###############################################################
#  Generated by:      Cadence Innovus 21.35-s114_1
#  OS:                Linux x86_64(Host ID CadenceRocky8)
#  Generated on:      Sat Mar  1 18:53:37 2025
#  Design:            scm_128x32
#  Command:           write_lef_abstract ram128_obspg.lef -obs_above_top_layer Metal4 -top_layer Metal3 -stripe_pins -pg_pin_layers {Metal4 Metal5}
###############################################################

VERSION 5.8 ;

BUSBITCHARS "[]" ;
DIVIDERCHAR "/" ;

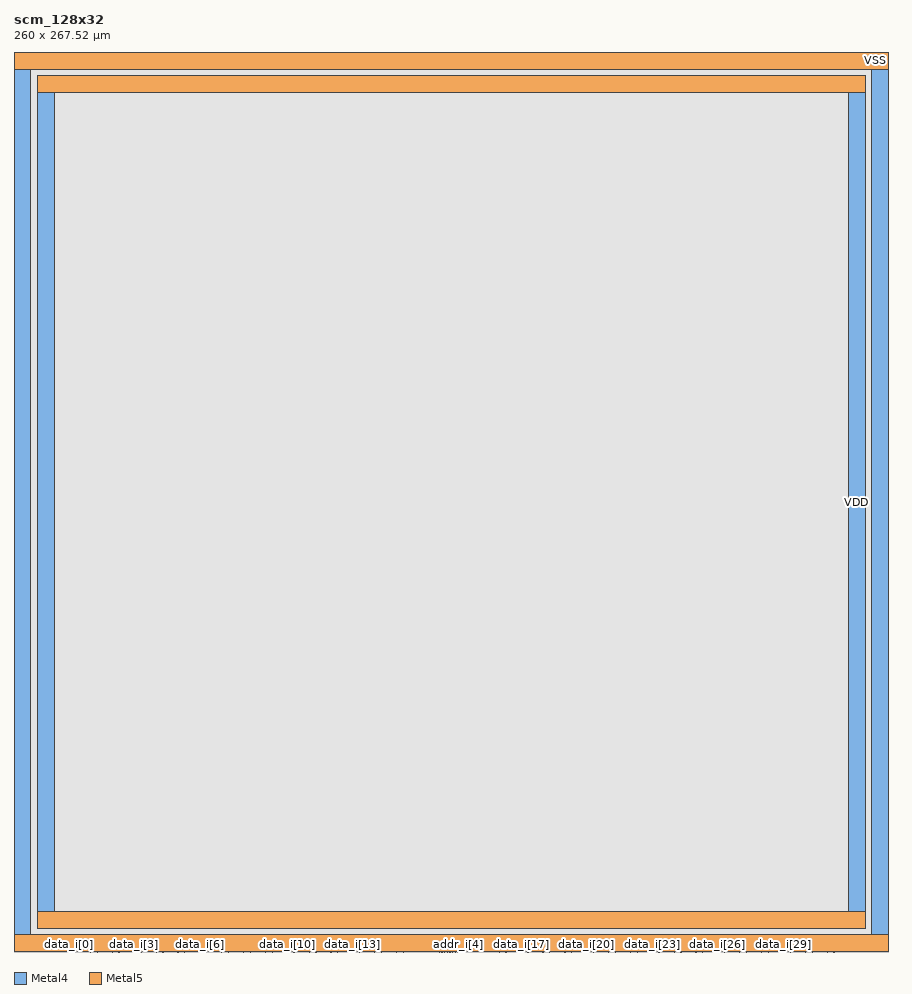
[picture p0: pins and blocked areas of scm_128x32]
MACRO scm_128x32
  CLASS BLOCK ;
  SIZE 260.000000 BY 267.520000 ;
  FOREIGN scm_128x32 0.000000 0.000000 ;
  ORIGIN 0 0 ;
  SYMMETRY X Y R90 ;
  PIN clk_i
    DIRECTION INPUT ;
    USE SIGNAL ;
    PORT
      LAYER Metal4 ;
        RECT 130.360000 0.000000 130.440000 0.250000 ;
    END
  END clk_i
  PIN req_i
    DIRECTION INPUT ;
    USE SIGNAL ;
    PORT
      LAYER Metal4 ;
        RECT 129.560000 0.000000 129.640000 0.250000 ;
    END
  END req_i
  PIN we_i
    DIRECTION INPUT ;
    USE SIGNAL ;
    PORT
      LAYER Metal4 ;
        RECT 131.160000 0.000000 131.240000 0.250000 ;
    END
  END we_i
  PIN data_i[31]
    DIRECTION INPUT ;
    USE SIGNAL ;
    PORT
      LAYER Metal4 ;
        RECT 241.710000 0.000000 241.790000 0.250000 ;
    END
  END data_i[31]
  PIN data_i[30]
    DIRECTION INPUT ;
    USE SIGNAL ;
    PORT
      LAYER Metal4 ;
        RECT 235.210000 0.000000 235.290000 0.250000 ;
    END
  END data_i[30]
  PIN data_i[29]
    DIRECTION INPUT ;
    USE SIGNAL ;
    PORT
      LAYER Metal4 ;
        RECT 228.710000 0.000000 228.790000 0.250000 ;
    END
  END data_i[29]
  PIN data_i[28]
    DIRECTION INPUT ;
    USE SIGNAL ;
    PORT
      LAYER Metal4 ;
        RECT 222.210000 0.000000 222.290000 0.250000 ;
    END
  END data_i[28]
  PIN data_i[27]
    DIRECTION INPUT ;
    USE SIGNAL ;
    PORT
      LAYER Metal4 ;
        RECT 215.710000 0.000000 215.790000 0.250000 ;
    END
  END data_i[27]
  PIN data_i[26]
    DIRECTION INPUT ;
    USE SIGNAL ;
    PORT
      LAYER Metal4 ;
        RECT 209.210000 0.000000 209.290000 0.250000 ;
    END
  END data_i[26]
  PIN data_i[25]
    DIRECTION INPUT ;
    USE SIGNAL ;
    PORT
      LAYER Metal4 ;
        RECT 202.710000 0.000000 202.790000 0.250000 ;
    END
  END data_i[25]
  PIN data_i[24]
    DIRECTION INPUT ;
    USE SIGNAL ;
    PORT
      LAYER Metal4 ;
        RECT 196.210000 0.000000 196.290000 0.250000 ;
    END
  END data_i[24]
  PIN data_i[23]
    DIRECTION INPUT ;
    USE SIGNAL ;
    PORT
      LAYER Metal4 ;
        RECT 189.710000 0.000000 189.790000 0.250000 ;
    END
  END data_i[23]
  PIN data_i[22]
    DIRECTION INPUT ;
    USE SIGNAL ;
    PORT
      LAYER Metal4 ;
        RECT 183.210000 0.000000 183.290000 0.250000 ;
    END
  END data_i[22]
  PIN data_i[21]
    DIRECTION INPUT ;
    USE SIGNAL ;
    PORT
      LAYER Metal4 ;
        RECT 176.710000 0.000000 176.790000 0.250000 ;
    END
  END data_i[21]
  PIN data_i[20]
    DIRECTION INPUT ;
    USE SIGNAL ;
    PORT
      LAYER Metal4 ;
        RECT 170.210000 0.000000 170.290000 0.250000 ;
    END
  END data_i[20]
  PIN data_i[19]
    DIRECTION INPUT ;
    USE SIGNAL ;
    PORT
      LAYER Metal4 ;
        RECT 163.710000 0.000000 163.790000 0.250000 ;
    END
  END data_i[19]
  PIN data_i[18]
    DIRECTION INPUT ;
    USE SIGNAL ;
    PORT
      LAYER Metal4 ;
        RECT 157.210000 0.000000 157.290000 0.250000 ;
    END
  END data_i[18]
  PIN data_i[17]
    DIRECTION INPUT ;
    USE SIGNAL ;
    PORT
      LAYER Metal4 ;
        RECT 150.710000 0.000000 150.790000 0.250000 ;
    END
  END data_i[17]
  PIN data_i[16]
    DIRECTION INPUT ;
    USE SIGNAL ;
    PORT
      LAYER Metal4 ;
        RECT 144.210000 0.000000 144.290000 0.250000 ;
    END
  END data_i[16]
  PIN data_i[15]
    DIRECTION INPUT ;
    USE SIGNAL ;
    PORT
      LAYER Metal4 ;
        RECT 113.710000 0.000000 113.790000 0.250000 ;
    END
  END data_i[15]
  PIN data_i[14]
    DIRECTION INPUT ;
    USE SIGNAL ;
    PORT
      LAYER Metal4 ;
        RECT 107.210000 0.000000 107.290000 0.250000 ;
    END
  END data_i[14]
  PIN data_i[13]
    DIRECTION INPUT ;
    USE SIGNAL ;
    PORT
      LAYER Metal4 ;
        RECT 100.710000 0.000000 100.790000 0.250000 ;
    END
  END data_i[13]
  PIN data_i[12]
    DIRECTION INPUT ;
    USE SIGNAL ;
    PORT
      LAYER Metal4 ;
        RECT 94.210000 0.000000 94.290000 0.250000 ;
    END
  END data_i[12]
  PIN data_i[11]
    DIRECTION INPUT ;
    USE SIGNAL ;
    PORT
      LAYER Metal4 ;
        RECT 87.710000 0.000000 87.790000 0.250000 ;
    END
  END data_i[11]
  PIN data_i[10]
    DIRECTION INPUT ;
    USE SIGNAL ;
    PORT
      LAYER Metal4 ;
        RECT 81.210000 0.000000 81.290000 0.250000 ;
    END
  END data_i[10]
  PIN data_i[9]
    DIRECTION INPUT ;
    USE SIGNAL ;
    PORT
      LAYER Metal4 ;
        RECT 74.710000 0.000000 74.790000 0.250000 ;
    END
  END data_i[9]
  PIN data_i[8]
    DIRECTION INPUT ;
    USE SIGNAL ;
    PORT
      LAYER Metal4 ;
        RECT 68.210000 0.000000 68.290000 0.250000 ;
    END
  END data_i[8]
  PIN data_i[7]
    DIRECTION INPUT ;
    USE SIGNAL ;
    PORT
      LAYER Metal4 ;
        RECT 61.710000 0.000000 61.790000 0.250000 ;
    END
  END data_i[7]
  PIN data_i[6]
    DIRECTION INPUT ;
    USE SIGNAL ;
    PORT
      LAYER Metal4 ;
        RECT 55.210000 0.000000 55.290000 0.250000 ;
    END
  END data_i[6]
  PIN data_i[5]
    DIRECTION INPUT ;
    USE SIGNAL ;
    PORT
      LAYER Metal4 ;
        RECT 48.710000 0.000000 48.790000 0.250000 ;
    END
  END data_i[5]
  PIN data_i[4]
    DIRECTION INPUT ;
    USE SIGNAL ;
    PORT
      LAYER Metal4 ;
        RECT 42.210000 0.000000 42.290000 0.250000 ;
    END
  END data_i[4]
  PIN data_i[3]
    DIRECTION INPUT ;
    USE SIGNAL ;
    PORT
      LAYER Metal4 ;
        RECT 35.710000 0.000000 35.790000 0.250000 ;
    END
  END data_i[3]
  PIN data_i[2]
    DIRECTION INPUT ;
    USE SIGNAL ;
    PORT
      LAYER Metal4 ;
        RECT 29.210000 0.000000 29.290000 0.250000 ;
    END
  END data_i[2]
  PIN data_i[1]
    DIRECTION INPUT ;
    USE SIGNAL ;
    PORT
      LAYER Metal4 ;
        RECT 22.710000 0.000000 22.790000 0.250000 ;
    END
  END data_i[1]
  PIN data_i[0]
    DIRECTION INPUT ;
    USE SIGNAL ;
    PORT
      LAYER Metal4 ;
        RECT 16.210000 0.000000 16.290000 0.250000 ;
    END
  END data_i[0]
  PIN addr_i[6]
    DIRECTION INPUT ;
    USE SIGNAL ;
    PORT
      LAYER Metal4 ;
        RECT 133.560000 0.000000 133.640000 0.250000 ;
    END
  END addr_i[6]
  PIN addr_i[5]
    DIRECTION INPUT ;
    USE SIGNAL ;
    PORT
      LAYER Metal4 ;
        RECT 132.760000 0.000000 132.840000 0.250000 ;
    END
  END addr_i[5]
  PIN addr_i[4]
    DIRECTION INPUT ;
    USE SIGNAL ;
    PORT
      LAYER Metal4 ;
        RECT 131.960000 0.000000 132.040000 0.250000 ;
    END
  END addr_i[4]
  PIN addr_i[3]
    DIRECTION INPUT ;
    USE SIGNAL ;
    PORT
      LAYER Metal4 ;
        RECT 128.760000 0.000000 128.840000 0.250000 ;
    END
  END addr_i[3]
  PIN addr_i[2]
    DIRECTION INPUT ;
    USE SIGNAL ;
    PORT
      LAYER Metal4 ;
        RECT 127.960000 0.000000 128.040000 0.250000 ;
    END
  END addr_i[2]
  PIN addr_i[1]
    DIRECTION INPUT ;
    USE SIGNAL ;
    PORT
      LAYER Metal4 ;
        RECT 127.160000 0.000000 127.240000 0.250000 ;
    END
  END addr_i[1]
  PIN addr_i[0]
    DIRECTION INPUT ;
    USE SIGNAL ;
    PORT
      LAYER Metal4 ;
        RECT 126.360000 0.000000 126.440000 0.250000 ;
    END
  END addr_i[0]
  PIN data_o[31]
    DIRECTION OUTPUT ;
    USE SIGNAL ;
    PORT
      LAYER Metal4 ;
        RECT 243.710000 0.000000 243.790000 0.250000 ;
    END
  END data_o[31]
  PIN data_o[30]
    DIRECTION OUTPUT ;
    USE SIGNAL ;
    PORT
      LAYER Metal4 ;
        RECT 237.210000 0.000000 237.290000 0.250000 ;
    END
  END data_o[30]
  PIN data_o[29]
    DIRECTION OUTPUT ;
    USE SIGNAL ;
    PORT
      LAYER Metal4 ;
        RECT 230.710000 0.000000 230.790000 0.250000 ;
    END
  END data_o[29]
  PIN data_o[28]
    DIRECTION OUTPUT ;
    USE SIGNAL ;
    PORT
      LAYER Metal4 ;
        RECT 224.210000 0.000000 224.290000 0.250000 ;
    END
  END data_o[28]
  PIN data_o[27]
    DIRECTION OUTPUT ;
    USE SIGNAL ;
    PORT
      LAYER Metal4 ;
        RECT 217.710000 0.000000 217.790000 0.250000 ;
    END
  END data_o[27]
  PIN data_o[26]
    DIRECTION OUTPUT ;
    USE SIGNAL ;
    PORT
      LAYER Metal4 ;
        RECT 211.210000 0.000000 211.290000 0.250000 ;
    END
  END data_o[26]
  PIN data_o[25]
    DIRECTION OUTPUT ;
    USE SIGNAL ;
    PORT
      LAYER Metal4 ;
        RECT 204.710000 0.000000 204.790000 0.250000 ;
    END
  END data_o[25]
  PIN data_o[24]
    DIRECTION OUTPUT ;
    USE SIGNAL ;
    PORT
      LAYER Metal4 ;
        RECT 198.210000 0.000000 198.290000 0.250000 ;
    END
  END data_o[24]
  PIN data_o[23]
    DIRECTION OUTPUT ;
    USE SIGNAL ;
    PORT
      LAYER Metal4 ;
        RECT 191.710000 0.000000 191.790000 0.250000 ;
    END
  END data_o[23]
  PIN data_o[22]
    DIRECTION OUTPUT ;
    USE SIGNAL ;
    PORT
      LAYER Metal4 ;
        RECT 185.210000 0.000000 185.290000 0.250000 ;
    END
  END data_o[22]
  PIN data_o[21]
    DIRECTION OUTPUT ;
    USE SIGNAL ;
    PORT
      LAYER Metal4 ;
        RECT 178.710000 0.000000 178.790000 0.250000 ;
    END
  END data_o[21]
  PIN data_o[20]
    DIRECTION OUTPUT ;
    USE SIGNAL ;
    PORT
      LAYER Metal4 ;
        RECT 172.210000 0.000000 172.290000 0.250000 ;
    END
  END data_o[20]
  PIN data_o[19]
    DIRECTION OUTPUT ;
    USE SIGNAL ;
    PORT
      LAYER Metal4 ;
        RECT 165.710000 0.000000 165.790000 0.250000 ;
    END
  END data_o[19]
  PIN data_o[18]
    DIRECTION OUTPUT ;
    USE SIGNAL ;
    PORT
      LAYER Metal4 ;
        RECT 159.210000 0.000000 159.290000 0.250000 ;
    END
  END data_o[18]
  PIN data_o[17]
    DIRECTION OUTPUT ;
    USE SIGNAL ;
    PORT
      LAYER Metal4 ;
        RECT 152.710000 0.000000 152.790000 0.250000 ;
    END
  END data_o[17]
  PIN data_o[16]
    DIRECTION OUTPUT ;
    USE SIGNAL ;
    PORT
      LAYER Metal4 ;
        RECT 146.210000 0.000000 146.290000 0.250000 ;
    END
  END data_o[16]
  PIN data_o[15]
    DIRECTION OUTPUT ;
    USE SIGNAL ;
    PORT
      LAYER Metal4 ;
        RECT 115.710000 0.000000 115.790000 0.250000 ;
    END
  END data_o[15]
  PIN data_o[14]
    DIRECTION OUTPUT ;
    USE SIGNAL ;
    PORT
      LAYER Metal4 ;
        RECT 109.210000 0.000000 109.290000 0.250000 ;
    END
  END data_o[14]
  PIN data_o[13]
    DIRECTION OUTPUT ;
    USE SIGNAL ;
    PORT
      LAYER Metal4 ;
        RECT 102.710000 0.000000 102.790000 0.250000 ;
    END
  END data_o[13]
  PIN data_o[12]
    DIRECTION OUTPUT ;
    USE SIGNAL ;
    PORT
      LAYER Metal4 ;
        RECT 96.210000 0.000000 96.290000 0.250000 ;
    END
  END data_o[12]
  PIN data_o[11]
    DIRECTION OUTPUT ;
    USE SIGNAL ;
    PORT
      LAYER Metal4 ;
        RECT 89.710000 0.000000 89.790000 0.250000 ;
    END
  END data_o[11]
  PIN data_o[10]
    DIRECTION OUTPUT ;
    USE SIGNAL ;
    PORT
      LAYER Metal4 ;
        RECT 83.210000 0.000000 83.290000 0.250000 ;
    END
  END data_o[10]
  PIN data_o[9]
    DIRECTION OUTPUT ;
    USE SIGNAL ;
    PORT
      LAYER Metal4 ;
        RECT 76.710000 0.000000 76.790000 0.250000 ;
    END
  END data_o[9]
  PIN data_o[8]
    DIRECTION OUTPUT ;
    USE SIGNAL ;
    PORT
      LAYER Metal4 ;
        RECT 70.210000 0.000000 70.290000 0.250000 ;
    END
  END data_o[8]
  PIN data_o[7]
    DIRECTION OUTPUT ;
    USE SIGNAL ;
    PORT
      LAYER Metal4 ;
        RECT 63.710000 0.000000 63.790000 0.250000 ;
    END
  END data_o[7]
  PIN data_o[6]
    DIRECTION OUTPUT ;
    USE SIGNAL ;
    PORT
      LAYER Metal4 ;
        RECT 57.210000 0.000000 57.290000 0.250000 ;
    END
  END data_o[6]
  PIN data_o[5]
    DIRECTION OUTPUT ;
    USE SIGNAL ;
    PORT
      LAYER Metal4 ;
        RECT 50.710000 0.000000 50.790000 0.250000 ;
    END
  END data_o[5]
  PIN data_o[4]
    DIRECTION OUTPUT ;
    USE SIGNAL ;
    PORT
      LAYER Metal4 ;
        RECT 44.210000 0.000000 44.290000 0.250000 ;
    END
  END data_o[4]
  PIN data_o[3]
    DIRECTION OUTPUT ;
    USE SIGNAL ;
    PORT
      LAYER Metal4 ;
        RECT 37.710000 0.000000 37.790000 0.250000 ;
    END
  END data_o[3]
  PIN data_o[2]
    DIRECTION OUTPUT ;
    USE SIGNAL ;
    PORT
      LAYER Metal4 ;
        RECT 31.210000 0.000000 31.290000 0.250000 ;
    END
  END data_o[2]
  PIN data_o[1]
    DIRECTION OUTPUT ;
    USE SIGNAL ;
    PORT
      LAYER Metal4 ;
        RECT 24.710000 0.000000 24.790000 0.250000 ;
    END
  END data_o[1]
  PIN data_o[0]
    DIRECTION OUTPUT ;
    USE SIGNAL ;
    PORT
      LAYER Metal4 ;
        RECT 18.210000 0.000000 18.290000 0.250000 ;
    END
  END data_o[0]
  PIN VSS
    DIRECTION INOUT ;
    USE GROUND ;

# P/G power stripe data as pin
    PORT
      LAYER Metal4 ;
        RECT 255.000000 0.060000 260.000000 267.460000 ;
        RECT 0.000000 0.060000 5.000000 267.460000 ;
      LAYER Metal5 ;
        RECT 0.000000 262.460000 260.000000 267.460000 ;
        RECT 0.000000 0.060000 260.000000 5.060000 ;
    END
# end of P/G power stripe data as pin

  END VSS
  PIN VDD
    DIRECTION INOUT ;
    USE POWER ;

# P/G power stripe data as pin
    PORT
      LAYER Metal4 ;
        RECT 248.000000 7.060000 253.000000 260.460000 ;
        RECT 7.000000 7.060000 12.000000 260.460000 ;
      LAYER Metal5 ;
        RECT 7.000000 255.460000 253.000000 260.460000 ;
        RECT 7.000000 7.060000 253.000000 12.060000 ;
    END
# end of P/G power stripe data as pin

  END VDD
  OBS
    LAYER Metal1 ;
      RECT 0.000000 0.000000 260.000000 267.520000 ;
    LAYER Metal2 ;
      RECT 0.000000 0.000000 260.000000 267.520000 ;
    LAYER Metal3 ;
      RECT 0.000000 0.000000 260.000000 267.520000 ;
  END
END scm_128x32

END LIBRARY
